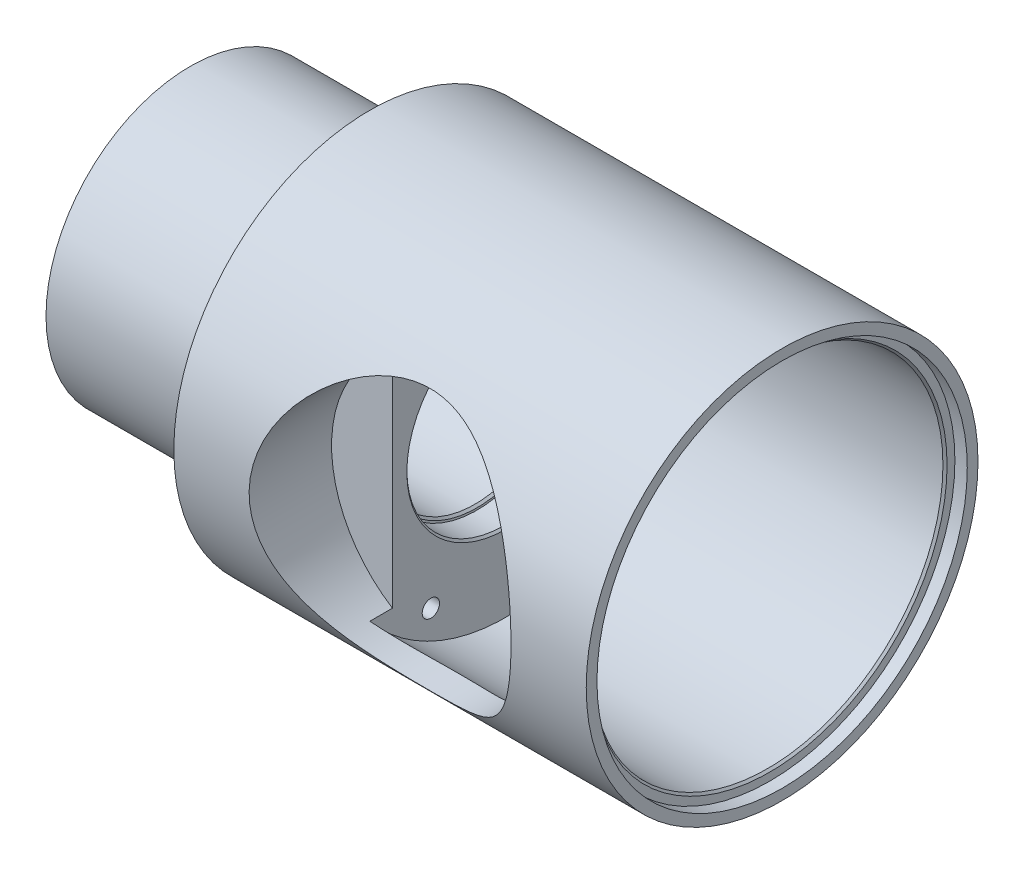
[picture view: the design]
ISO-10303-21;
HEADER;
FILE_DESCRIPTION(('STEP AP214'),'2;1');
FILE_NAME('part.step','',(''),(''),'','','');
FILE_SCHEMA(('AUTOMOTIVE_DESIGN { 1 0 10303 214 1 1 1 1 }'));
ENDSEC;
DATA;
#1=APPLICATION_CONTEXT('core data for automotive mechanical design processes');
#2=APPLICATION_PROTOCOL_DEFINITION('international standard','automotive_design',2000,#1);
#3=PRODUCT_CONTEXT('',#1,'mechanical');
#4=PRODUCT('Part','Part','',(#3));
#5=PRODUCT_RELATED_PRODUCT_CATEGORY('part','',(#4));
#6=PRODUCT_DEFINITION_FORMATION('','',#4);
#7=PRODUCT_DEFINITION_CONTEXT('part definition',#1,'design');
#8=PRODUCT_DEFINITION('design','',#6,#7);
#9=PRODUCT_DEFINITION_SHAPE('','',#8);
#10=(LENGTH_UNIT() NAMED_UNIT(*) SI_UNIT(.MILLI.,.METRE.));
#11=(NAMED_UNIT(*) PLANE_ANGLE_UNIT() SI_UNIT($,.RADIAN.));
#12=(NAMED_UNIT(*) SI_UNIT($,.STERADIAN.) SOLID_ANGLE_UNIT());
#13=UNCERTAINTY_MEASURE_WITH_UNIT(LENGTH_MEASURE(1.E-05),#10,'distance_accuracy_value','');
#14=(GEOMETRIC_REPRESENTATION_CONTEXT(3) GLOBAL_UNCERTAINTY_ASSIGNED_CONTEXT((#13)) GLOBAL_UNIT_ASSIGNED_CONTEXT((#10,
#11,#12)) REPRESENTATION_CONTEXT('',''));
#15=CARTESIAN_POINT('',(0.,0.,0.));
#16=DIRECTION('',(0.,0.,1.));
#17=DIRECTION('',(1.,0.,0.));
#18=AXIS2_PLACEMENT_3D('',#15,#16,#17);
#19=CARTESIAN_POINT('',(100.,0.,0.));
#20=DIRECTION('',(-1.,0.,0.));
#21=DIRECTION('',(0.,0.,1.));
#22=AXIS2_PLACEMENT_3D('',#19,#20,#21);
#23=CYLINDRICAL_SURFACE('',#22,42.5);
#24=CARTESIAN_POINT('',(96.5,0.,0.));
#25=DIRECTION('',(1.,0.,0.));
#26=DIRECTION('',(0.,0.,-1.));
#27=AXIS2_PLACEMENT_3D('',#24,#25,#26);
#28=CIRCLE('',#27,42.5);
#29=CARTESIAN_POINT('',(96.5,0.,-42.5));
#30=VERTEX_POINT('',#29);
#31=EDGE_CURVE('E47',#30,#30,#28,.T.);
#32=ORIENTED_EDGE('',*,*,#31,.T.);
#33=EDGE_LOOP('',(#32));
#34=FACE_BOUND('',#33,.T.);
#35=CARTESIAN_POINT('',(33.,26.8153407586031,32.9725264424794));
#36=CARTESIAN_POINT('',(33.3044816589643,27.0083646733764,32.815549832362));
#37=CARTESIAN_POINT('',(33.612655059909,27.1964727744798,32.6597490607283));
#38=CARTESIAN_POINT('',(34.236438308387,27.5627200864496,32.3512561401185));
#39=CARTESIAN_POINT('',(34.5520488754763,27.7408583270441,32.1985642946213));
#40=CARTESIAN_POINT('',(35.5108638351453,28.2605115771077,31.7459377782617));
#41=CARTESIAN_POINT('',(36.1652526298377,28.5867577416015,31.4518681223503));
#42=CARTESIAN_POINT('',(37.5111254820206,29.2000660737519,30.8833788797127));
#43=CARTESIAN_POINT('',(38.2029549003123,29.4866231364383,30.6092305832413));
#44=CARTESIAN_POINT('',(39.6154730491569,30.013190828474,30.0930934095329));
#45=CARTESIAN_POINT('',(40.3361453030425,30.2532275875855,29.8510865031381));
#46=CARTESIAN_POINT('',(41.6673684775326,30.6433808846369,29.4498945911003));
#47=CARTESIAN_POINT('',(42.2733328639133,30.8019186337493,29.2836835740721));
#48=CARTESIAN_POINT('',(43.5013379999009,31.0841865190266,28.9838887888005));
#49=CARTESIAN_POINT('',(44.123378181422,31.2079178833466,28.8503038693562));
#50=CARTESIAN_POINT('',(45.3774268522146,31.4180904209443,28.6212811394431));
#51=CARTESIAN_POINT('',(46.0093698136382,31.5047152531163,28.5256556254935));
#52=CARTESIAN_POINT('',(47.2822072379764,31.6399366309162,28.3756004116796));
#53=CARTESIAN_POINT('',(47.9231013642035,31.6885346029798,28.3211691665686));
#54=CARTESIAN_POINT('',(49.212934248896,31.7468476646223,28.2557897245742));
#55=CARTESIAN_POINT('',(49.861898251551,31.7563176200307,28.2451156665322));
#56=CARTESIAN_POINT('',(51.1583574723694,31.7354856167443,28.2685191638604));
#57=CARTESIAN_POINT('',(51.8058527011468,31.7051839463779,28.3025963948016));
#58=CARTESIAN_POINT('',(53.0952798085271,31.6053910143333,28.413989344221));
#59=CARTESIAN_POINT('',(53.7371985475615,31.5358242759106,28.4913883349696));
#60=CARTESIAN_POINT('',(55.009649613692,31.3588706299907,28.6860316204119));
#61=CARTESIAN_POINT('',(55.6401803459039,31.2514784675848,28.8032814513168));
#62=CARTESIAN_POINT('',(57.0171653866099,30.9743953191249,29.1013135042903));
#63=CARTESIAN_POINT('',(57.7601713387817,30.7963592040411,29.2902654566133));
#64=CARTESIAN_POINT('',(59.2202971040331,30.3911696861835,29.7104659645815));
#65=CARTESIAN_POINT('',(59.9374105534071,30.1640043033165,29.9417248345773));
#66=CARTESIAN_POINT('',(61.3448167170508,29.6633874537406,30.4377683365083));
#67=CARTESIAN_POINT('',(62.0350577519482,29.3898517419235,30.7026137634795));
#68=CARTESIAN_POINT('',(63.3863525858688,28.799510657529,31.2570352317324));
#69=CARTESIAN_POINT('',(64.0474046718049,28.4827027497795,31.5466127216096));
#70=CARTESIAN_POINT('',(65.5558197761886,27.695215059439,32.2426020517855));
#71=CARTESIAN_POINT('',(66.3917215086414,27.2084714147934,32.655749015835));
#72=CARTESIAN_POINT('',(68.0105141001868,26.1650818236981,33.4975866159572));
#73=CARTESIAN_POINT('',(68.7933891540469,25.6084151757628,33.9262818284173));
#74=CARTESIAN_POINT('',(70.3053771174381,24.4269370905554,34.7866247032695));
#75=CARTESIAN_POINT('',(71.0344469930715,23.8020720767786,35.218274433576));
#76=CARTESIAN_POINT('',(72.4357046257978,22.4861112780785,36.072707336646));
#77=CARTESIAN_POINT('',(73.1078989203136,21.7950231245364,36.4954915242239));
#78=CARTESIAN_POINT('',(74.3963690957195,20.3427813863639,37.3245969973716));
#79=CARTESIAN_POINT('',(75.0122101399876,19.5811615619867,37.7307787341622));
#80=CARTESIAN_POINT('',(76.1774518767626,17.9936771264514,38.5131160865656));
#81=CARTESIAN_POINT('',(76.7268446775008,17.1678049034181,38.8892681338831));
#82=CARTESIAN_POINT('',(77.4952335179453,15.8846665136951,39.4226032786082));
#83=CARTESIAN_POINT('',(77.7418553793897,15.4500335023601,39.595071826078));
#84=CARTESIAN_POINT('',(78.2159513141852,14.5661932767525,39.9286738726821));
#85=CARTESIAN_POINT('',(78.4434266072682,14.1169869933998,40.0898080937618));
#86=CARTESIAN_POINT('',(78.8781436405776,13.204937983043,40.3993987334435));
#87=CARTESIAN_POINT('',(79.0853960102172,12.7421025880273,40.5478618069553));
#88=CARTESIAN_POINT('',(79.4788601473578,11.8033226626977,40.8310181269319));
#89=CARTESIAN_POINT('',(79.6650668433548,11.3273750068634,40.9657080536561));
#90=CARTESIAN_POINT('',(80.087375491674,10.165412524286,41.2723723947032));
#91=CARTESIAN_POINT('',(80.3125546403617,9.47341468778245,41.4369361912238));
#92=CARTESIAN_POINT('',(80.7162066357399,8.06911355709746,41.7331287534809));
#93=CARTESIAN_POINT('',(80.8946904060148,7.35681505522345,41.8647652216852));
#94=CARTESIAN_POINT('',(81.1255926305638,6.27659556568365,42.0355490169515));
#95=CARTESIAN_POINT('',(81.1964172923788,5.91459909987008,42.0880276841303));
#96=CARTESIAN_POINT('',(81.3255693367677,5.18725605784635,42.1838466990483));
#97=CARTESIAN_POINT('',(81.3838990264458,4.82191011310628,42.2271887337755));
#98=CARTESIAN_POINT('',(81.5398253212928,3.72160807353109,42.3431592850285));
#99=CARTESIAN_POINT('',(81.6183742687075,2.98231724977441,42.401743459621));
#100=CARTESIAN_POINT('',(81.7235000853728,1.49618226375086,42.4801924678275));
#101=CARTESIAN_POINT('',(81.7499437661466,0.74932363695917,42.4999580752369));
#102=CARTESIAN_POINT('',(81.7500560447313,-0.744422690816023,42.5000417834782));
#103=CARTESIAN_POINT('',(81.7237248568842,-1.49131039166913,42.4803600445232));
#104=CARTESIAN_POINT('',(81.618697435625,-2.97943207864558,42.4019847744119));
#105=CARTESIAN_POINT('',(81.5399924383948,-3.72066509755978,42.3432847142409));
#106=CARTESIAN_POINT('',(81.3314378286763,-5.19186855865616,42.188169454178));
#107=CARTESIAN_POINT('',(81.2015885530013,-5.92183907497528,42.0917545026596));
#108=CARTESIAN_POINT('',(80.8979550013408,-7.34078972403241,41.867183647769));
#109=CARTESIAN_POINT('',(80.7258286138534,-8.03031734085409,41.7402285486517));
#110=CARTESIAN_POINT('',(80.3378281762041,-9.39035484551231,41.4554455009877));
#111=CARTESIAN_POINT('',(80.1219554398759,-10.0608653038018,41.2976184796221));
#112=CARTESIAN_POINT('',(79.648862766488,-11.3797338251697,40.9538295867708));
#113=CARTESIAN_POINT('',(79.3916390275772,-12.0280898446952,40.7678651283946));
#114=CARTESIAN_POINT('',(78.8383817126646,-13.3000503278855,40.370814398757));
#115=CARTESIAN_POINT('',(78.542345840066,-13.9236533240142,40.1597266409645));
#116=CARTESIAN_POINT('',(77.8800029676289,-15.2100737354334,39.691578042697));
#117=CARTESIAN_POINT('',(77.5095594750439,-15.8698499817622,39.4320142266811));
#118=CARTESIAN_POINT('',(76.7272772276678,-17.1546188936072,38.8902971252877));
#119=CARTESIAN_POINT('',(76.3154359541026,-17.7796094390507,38.6081424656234));
#120=CARTESIAN_POINT('',(75.4529052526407,-18.9938708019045,38.025473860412));
#121=CARTESIAN_POINT('',(75.0021884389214,-19.5831159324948,37.7249470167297));
#122=CARTESIAN_POINT('',(74.0645874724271,-20.7244702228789,37.1101951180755));
#123=CARTESIAN_POINT('',(73.5777015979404,-21.2765776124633,36.795969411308));
#124=CARTESIAN_POINT('',(72.4710049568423,-22.4474122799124,36.0959193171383));
#125=CARTESIAN_POINT('',(71.8438326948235,-23.0580194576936,35.7081218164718));
#126=CARTESIAN_POINT('',(70.5429813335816,-24.2241970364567,34.9275066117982));
#127=CARTESIAN_POINT('',(69.8692932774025,-24.7797567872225,34.5346879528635));
#128=CARTESIAN_POINT('',(68.4767492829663,-25.8347768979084,33.7527119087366));
#129=CARTESIAN_POINT('',(67.7578733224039,-26.3342121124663,33.3635562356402));
#130=CARTESIAN_POINT('',(66.2761509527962,-27.2748840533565,32.599045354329));
#131=CARTESIAN_POINT('',(65.5133145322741,-27.7161339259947,32.2236870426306));
#132=CARTESIAN_POINT('',(64.0996929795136,-28.4563742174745,31.5702079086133));
#133=CARTESIAN_POINT('',(63.4566756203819,-28.766225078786,31.28756252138));
#134=CARTESIAN_POINT('',(62.1429067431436,-29.3449733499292,30.7454014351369));
#135=CARTESIAN_POINT('',(61.4721556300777,-29.613871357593,30.4858853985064));
#136=CARTESIAN_POINT('',(60.1048873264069,-30.1078266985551,29.9981520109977));
#137=CARTESIAN_POINT('',(59.4084130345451,-30.3329534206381,29.7698852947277));
#138=CARTESIAN_POINT('',(57.990637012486,-30.736867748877,29.3526733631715));
#139=CARTESIAN_POINT('',(57.2693416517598,-30.9156671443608,29.163718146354));
#140=CARTESIAN_POINT('',(55.9476954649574,-31.1937604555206,28.8657650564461));
#141=CARTESIAN_POINT('',(55.3510652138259,-31.3017514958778,28.7483654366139));
#142=CARTESIAN_POINT('',(54.146828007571,-31.4839158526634,28.5487546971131));
#143=CARTESIAN_POINT('',(53.5392224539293,-31.5580934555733,28.4665391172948));
#144=CARTESIAN_POINT('',(52.3179935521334,-31.6711958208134,28.3406521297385));
#145=CARTESIAN_POINT('',(51.7043850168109,-31.710192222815,28.2969023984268));
#146=CARTESIAN_POINT('',(50.4743654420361,-31.7524191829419,28.2495117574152));
#147=CARTESIAN_POINT('',(49.8579543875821,-31.7556495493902,28.2458710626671));
#148=CARTESIAN_POINT('',(48.6278025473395,-31.7262933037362,28.2788397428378));
#149=CARTESIAN_POINT('',(48.0140594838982,-31.6937485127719,28.3154021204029));
#150=CARTESIAN_POINT('',(46.793028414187,-31.5935619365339,28.4271422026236));
#151=CARTESIAN_POINT('',(46.1857405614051,-31.525919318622,28.5023208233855));
#152=CARTESIAN_POINT('',(44.9784122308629,-31.3563342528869,28.688781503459));
#153=CARTESIAN_POINT('',(44.3784246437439,-31.2542183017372,28.8002460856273));
#154=CARTESIAN_POINT('',(43.1919250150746,-31.0173947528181,29.0551443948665));
#155=CARTESIAN_POINT('',(42.6054135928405,-30.882685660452,29.1985795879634));
#156=CARTESIAN_POINT('',(41.2005638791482,-30.5182001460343,29.580156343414));
#157=CARTESIAN_POINT('',(40.3902262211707,-30.2723952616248,29.8325796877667));
#158=CARTESIAN_POINT('',(38.8041722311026,-29.7224123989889,30.3805671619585));
#159=CARTESIAN_POINT('',(38.0284916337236,-29.4181758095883,30.6761745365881));
#160=CARTESIAN_POINT('',(36.5222538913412,-28.759015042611,31.2949033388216));
#161=CARTESIAN_POINT('',(35.7912883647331,-28.4046973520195,31.6176791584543));
#162=CARTESIAN_POINT('',(34.7230823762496,-27.8359579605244,32.1165532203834));
#163=CARTESIAN_POINT('',(34.3720780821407,-27.6403947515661,32.285109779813));
#164=CARTESIAN_POINT('',(33.6792081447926,-27.2370112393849,32.6261397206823));
#165=CARTESIAN_POINT('',(33.3373412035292,-27.0291926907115,32.7986125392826));
#166=CARTESIAN_POINT('',(33.,-26.8153407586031,32.9725264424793));
#167=B_SPLINE_CURVE_WITH_KNOTS('',3,(#35,#36,#37,#38,#39,#40,#41,#42,#43,#44,#45,#46,#47,#48,
#49,#50,#51,#52,#53,#54,#55,#56,#57,#58,#59,#60,#61,#62,#63,#64,#65,#66,#67,#68,#69,#70,#71,#72,
#73,#74,#75,#76,#77,#78,#79,#80,#81,#82,#83,#84,#85,#86,#87,#88,#89,#90,#91,#92,#93,#94,#95,#96,
#97,#98,#99,#100,#101,#102,#103,#104,#105,#106,#107,#108,#109,#110,#111,#112,#113,#114,#115,
#116,#117,#118,#119,#120,#121,#122,#123,#124,#125,#126,#127,#128,#129,#130,#131,#132,#133,#134,
#135,#136,#137,#138,#139,#140,#141,#142,#143,#144,#145,#146,#147,#148,#149,#150,#151,#152,#153,
#154,#155,#156,#157,#158,#159,#160,#161,#162,#163,#164,#165,#166),.UNSPECIFIED.,.F.,.F.,(4,2,2,
2,2,2,2,2,2,2,2,2,2,2,2,2,2,2,2,2,2,2,2,2,2,2,2,2,2,2,2,2,2,2,2,2,2,2,2,2,2,2,2,2,2,2,2,2,2,2,2,
2,2,2,2,2,2,2,2,2,2,2,2,2,2,4),(0.,1.17950720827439,2.35912900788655,4.72146779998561,
7.11154645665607,9.50027872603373,11.4426474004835,13.3849475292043,15.3175199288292,
17.2500198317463,19.1946085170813,21.1391831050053,23.0875084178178,25.0361045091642,
27.3937212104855,29.751913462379,32.114436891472,34.4770987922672,37.6283786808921,
40.7805937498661,43.9353032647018,47.0896496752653,50.2665812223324,53.4438897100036,
55.0292971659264,56.6146035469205,58.1990721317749,59.7839217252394,62.0197684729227,
64.2550917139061,65.3725185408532,66.4897388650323,68.723961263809,70.9638872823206,
73.2038042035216,75.444096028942,77.684373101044,79.8478870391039,82.0113360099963,
84.1749840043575,86.3387600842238,88.7362833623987,91.1339526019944,93.5333248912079,
95.9328114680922,98.8020819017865,101.671906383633,104.543011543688,107.41346689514,
109.714852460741,112.016204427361,114.31387786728,116.610966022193,118.461882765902,
120.312564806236,122.15946973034,124.006384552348,125.851142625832,127.695944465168,
129.550173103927,131.404486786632,134.050955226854,136.700092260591,139.319530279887,
140.626480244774,141.933243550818),.UNSPECIFIED.);
#168=CARTESIAN_POINT('',(33.,26.8153407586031,32.9725264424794));
#169=VERTEX_POINT('',#168);
#170=CARTESIAN_POINT('',(33.,-26.8153407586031,32.9725264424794));
#171=VERTEX_POINT('',#170);
#172=EDGE_CURVE('E60',#169,#171,#167,.T.);
#173=ORIENTED_EDGE('',*,*,#172,.F.);
#174=CARTESIAN_POINT('',(33.,0.,0.));
#175=DIRECTION('',(-1.,0.,0.));
#176=DIRECTION('',(0.,0.,1.));
#177=AXIS2_PLACEMENT_3D('',#174,#175,#176);
#178=CIRCLE('',#177,42.5);
#179=EDGE_CURVE('E181',#169,#171,#178,.T.);
#180=ORIENTED_EDGE('',*,*,#179,.T.);
#181=EDGE_LOOP('',(#173,#180));
#182=FACE_BOUND('',#181,.T.);
#183=ADVANCED_FACE('F39',(#34,#182),#23,.F.);
#184=CARTESIAN_POINT('',(-46.,0.,0.));
#185=DIRECTION('',(1.,0.,0.));
#186=DIRECTION('',(0.,0.,-1.));
#187=AXIS2_PLACEMENT_3D('',#184,#185,#186);
#188=CYLINDRICAL_SURFACE('',#187,35.);
#189=CARTESIAN_POINT('',(0.,0.,0.));
#190=DIRECTION('',(-1.,0.,0.));
#191=DIRECTION('',(0.,0.,1.));
#192=AXIS2_PLACEMENT_3D('',#189,#190,#191);
#193=CIRCLE('',#192,35.);
#194=CARTESIAN_POINT('',(0.,0.,35.));
#195=VERTEX_POINT('',#194);
#196=EDGE_CURVE('E95',#195,#195,#193,.T.);
#197=ORIENTED_EDGE('',*,*,#196,.T.);
#198=EDGE_LOOP('',(#197));
#199=FACE_BOUND('',#198,.T.);
#200=CARTESIAN_POINT('',(-43.5,0.,0.));
#201=DIRECTION('',(-1.,0.,0.));
#202=DIRECTION('',(0.,0.,1.));
#203=AXIS2_PLACEMENT_3D('',#200,#201,#202);
#204=CIRCLE('',#203,35.);
#205=CARTESIAN_POINT('',(-43.5,0.,35.));
#206=VERTEX_POINT('',#205);
#207=EDGE_CURVE('E213',#206,#206,#204,.T.);
#208=ORIENTED_EDGE('',*,*,#207,.F.);
#209=EDGE_LOOP('',(#208));
#210=FACE_BOUND('',#209,.T.);
#211=ADVANCED_FACE('F168',(#199,#210),#188,.T.);
#212=CARTESIAN_POINT('',(-23.,0.,0.));
#213=DIRECTION('',(-1.,0.,0.));
#214=DIRECTION('',(0.,0.,1.));
#215=AXIS2_PLACEMENT_3D('',#212,#213,#214);
#216=CYLINDRICAL_SURFACE('',#215,21.);
#217=CARTESIAN_POINT('',(-23.,0.,0.));
#218=DIRECTION('',(-1.,0.,0.));
#219=DIRECTION('',(0.,0.,1.));
#220=AXIS2_PLACEMENT_3D('',#217,#218,#219);
#221=CIRCLE('',#220,21.);
#222=CARTESIAN_POINT('',(-23.,0.,21.));
#223=VERTEX_POINT('',#222);
#224=EDGE_CURVE('E92',#223,#223,#221,.T.);
#225=ORIENTED_EDGE('',*,*,#224,.F.);
#226=EDGE_LOOP('',(#225));
#227=FACE_BOUND('',#226,.T.);
#228=CARTESIAN_POINT('',(-43.5,0.,0.));
#229=DIRECTION('',(-1.,0.,0.));
#230=DIRECTION('',(0.,0.,1.));
#231=AXIS2_PLACEMENT_3D('',#228,#229,#230);
#232=CIRCLE('',#231,21.);
#233=CARTESIAN_POINT('',(-43.5,0.,21.));
#234=VERTEX_POINT('',#233);
#235=EDGE_CURVE('E210',#234,#234,#232,.F.);
#236=ORIENTED_EDGE('',*,*,#235,.F.);
#237=EDGE_LOOP('',(#236));
#238=FACE_BOUND('',#237,.T.);
#239=ADVANCED_FACE('F173',(#227,#238),#216,.F.);
#240=CARTESIAN_POINT('',(100.,0.,0.));
#241=DIRECTION('',(1.,0.,0.));
#242=DIRECTION('',(0.,0.,-1.));
#243=AXIS2_PLACEMENT_3D('',#240,#241,#242);
#244=PLANE('',#243);
#245=CARTESIAN_POINT('',(100.,0.,0.));
#246=DIRECTION('',(1.,0.,0.));
#247=DIRECTION('',(0.,0.,-1.));
#248=AXIS2_PLACEMENT_3D('',#245,#246,#247);
#249=CIRCLE('',#248,44.9);
#250=CARTESIAN_POINT('',(100.,0.,-44.9));
#251=VERTEX_POINT('',#250);
#252=EDGE_CURVE('E225',#251,#251,#249,.T.);
#253=ORIENTED_EDGE('',*,*,#252,.F.);
#254=EDGE_LOOP('',(#253));
#255=FACE_BOUND('',#254,.T.);
#256=CARTESIAN_POINT('',(100.,0.,0.));
#257=DIRECTION('',(1.,0.,0.));
#258=DIRECTION('',(0.,0.,-1.));
#259=AXIS2_PLACEMENT_3D('',#256,#257,#258);
#260=CIRCLE('',#259,47.5);
#261=CARTESIAN_POINT('',(100.,0.,-47.5));
#262=VERTEX_POINT('',#261);
#263=EDGE_CURVE('E189',#262,#262,#260,.T.);
#264=ORIENTED_EDGE('',*,*,#263,.T.);
#265=EDGE_LOOP('',(#264));
#266=FACE_BOUND('',#265,.T.);
#267=ADVANCED_FACE('F254',(#255,#266),#244,.T.);
#268=CARTESIAN_POINT('',(0.,0.,0.));
#269=DIRECTION('',(1.,0.,0.));
#270=DIRECTION('',(0.,0.,-1.));
#271=AXIS2_PLACEMENT_3D('',#268,#269,#270);
#272=PLANE('',#271);
#273=CARTESIAN_POINT('',(0.,0.,0.));
#274=DIRECTION('',(1.,0.,0.));
#275=DIRECTION('',(0.,0.,-1.));
#276=AXIS2_PLACEMENT_3D('',#273,#274,#275);
#277=CIRCLE('',#276,47.5);
#278=CARTESIAN_POINT('',(0.,0.,-47.5));
#279=VERTEX_POINT('',#278);
#280=EDGE_CURVE('E187',#279,#279,#277,.T.);
#281=ORIENTED_EDGE('',*,*,#280,.F.);
#282=EDGE_LOOP('',(#281));
#283=FACE_BOUND('',#282,.T.);
#284=ORIENTED_EDGE('',*,*,#196,.F.);
#285=EDGE_LOOP('',(#284));
#286=FACE_BOUND('',#285,.T.);
#287=ADVANCED_FACE('F163',(#283,#286),#272,.F.);
#288=CARTESIAN_POINT('',(100.,0.,0.));
#289=DIRECTION('',(-1.,0.,0.));
#290=DIRECTION('',(0.,0.,1.));
#291=AXIS2_PLACEMENT_3D('',#288,#289,#290);
#292=CYLINDRICAL_SURFACE('',#291,47.5);
#293=CARTESIAN_POINT('',(81.75,0.,47.5));
#294=CARTESIAN_POINT('',(81.7500004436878,-0.797202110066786,47.500000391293));
#295=CARTESIAN_POINT('',(81.7199353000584,-1.59439947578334,47.4798883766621));
#296=CARTESIAN_POINT('',(81.6001519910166,-3.18226729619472,47.3999485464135));
#297=CARTESIAN_POINT('',(81.5104343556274,-3.97293780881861,47.3401210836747));
#298=CARTESIAN_POINT('',(81.2726769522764,-5.54183673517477,47.1821993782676));
#299=CARTESIAN_POINT('',(81.1246161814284,-6.32006056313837,47.0840913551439));
#300=CARTESIAN_POINT('',(80.772297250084,-7.85816597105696,46.851939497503));
#301=CARTESIAN_POINT('',(80.5680382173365,-8.61804726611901,46.7178951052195));
#302=CARTESIAN_POINT('',(80.107098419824,-10.1110159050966,46.4176094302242));
#303=CARTESIAN_POINT('',(79.8506726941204,-10.8442138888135,46.2515249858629));
#304=CARTESIAN_POINT('',(79.2877461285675,-12.2836355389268,45.8902276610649));
#305=CARTESIAN_POINT('',(78.9812455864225,-12.9898593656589,45.6950149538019));
#306=CARTESIAN_POINT('',(78.321197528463,-14.372158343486,45.2792670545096));
#307=CARTESIAN_POINT('',(77.9676497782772,-15.0482333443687,45.0587317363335));
#308=CARTESIAN_POINT('',(77.2164491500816,-16.367769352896,44.5963560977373));
#309=CARTESIAN_POINT('',(76.8187941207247,-17.0112287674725,44.3545147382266));
#310=CARTESIAN_POINT('',(75.9465363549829,-18.3168620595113,43.8323849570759));
#311=CARTESIAN_POINT('',(75.4682660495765,-18.9759769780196,43.5505758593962));
#312=CARTESIAN_POINT('',(74.4661227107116,-20.2516512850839,42.9722140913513));
#313=CARTESIAN_POINT('',(73.9422476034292,-20.8682087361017,42.6756607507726));
#314=CARTESIAN_POINT('',(72.85078583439,-22.0580305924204,42.073014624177));
#315=CARTESIAN_POINT('',(72.2831415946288,-22.6312359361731,41.7669095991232));
#316=CARTESIAN_POINT('',(71.1068978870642,-23.7320520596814,41.1513967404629));
#317=CARTESIAN_POINT('',(70.4982960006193,-24.259660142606,40.841988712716));
#318=CARTESIAN_POINT('',(69.142006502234,-25.347928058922,40.1771197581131));
#319=CARTESIAN_POINT('',(68.3875818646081,-25.9005256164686,39.8221504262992));
#320=CARTESIAN_POINT('',(66.8280869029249,-26.939863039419,39.1265248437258));
#321=CARTESIAN_POINT('',(66.0230050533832,-27.4265878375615,38.7858718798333));
#322=CARTESIAN_POINT('',(64.3656084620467,-28.3298662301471,38.131082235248));
#323=CARTESIAN_POINT('',(63.5133598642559,-28.7465149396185,37.8169099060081));
#324=CARTESIAN_POINT('',(61.7636735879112,-29.5057088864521,37.2275996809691));
#325=CARTESIAN_POINT('',(60.8662579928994,-29.8482899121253,36.9524429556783));
#326=CARTESIAN_POINT('',(59.2971336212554,-30.3660442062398,36.5271244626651));
#327=CARTESIAN_POINT('',(58.635437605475,-30.5609551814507,36.3638542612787));
#328=CARTESIAN_POINT('',(57.2941343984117,-30.9085391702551,36.0688818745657));
#329=CARTESIAN_POINT('',(56.614530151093,-31.0612190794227,35.9371745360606));
#330=CARTESIAN_POINT('',(55.2418790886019,-31.3220764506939,35.7100475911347));
#331=CARTESIAN_POINT('',(54.5488539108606,-31.4303201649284,35.6145739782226));
#332=CARTESIAN_POINT('',(53.1528202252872,-31.6008960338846,35.4633113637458));
#333=CARTESIAN_POINT('',(52.4498116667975,-31.663227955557,35.4075225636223));
#334=CARTESIAN_POINT('',(51.0361244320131,-31.7410168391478,35.3378076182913));
#335=CARTESIAN_POINT('',(50.3254259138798,-31.7562750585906,35.3240589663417));
#336=CARTESIAN_POINT('',(48.9050808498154,-31.7390624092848,35.3395251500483));
#337=CARTESIAN_POINT('',(48.1954343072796,-31.7065913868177,35.3687401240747));
#338=CARTESIAN_POINT('',(46.7823583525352,-31.5944941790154,35.4689092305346));
#339=CARTESIAN_POINT('',(46.0789339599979,-31.5148329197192,35.5398944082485));
#340=CARTESIAN_POINT('',(44.6839107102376,-31.3097240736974,35.7207191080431));
#341=CARTESIAN_POINT('',(43.9923120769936,-31.1842756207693,35.8305593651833));
#342=CARTESIAN_POINT('',(42.6563084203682,-30.8962500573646,36.0791647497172));
#343=CARTESIAN_POINT('',(42.0111891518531,-30.7356259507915,36.216383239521));
#344=CARTESIAN_POINT('',(40.7380318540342,-30.376243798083,36.5183359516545));
#345=CARTESIAN_POINT('',(40.1100005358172,-30.1774710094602,36.6830808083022));
#346=CARTESIAN_POINT('',(38.8732274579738,-29.743687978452,37.0356732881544));
#347=CARTESIAN_POINT('',(38.2644876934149,-29.5086740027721,37.2235232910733));
#348=CARTESIAN_POINT('',(37.0679273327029,-29.0042327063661,37.6179074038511));
#349=CARTESIAN_POINT('',(36.4801021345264,-28.7348130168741,37.8244373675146));
#350=CARTESIAN_POINT('',(35.2083604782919,-28.1046463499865,38.2957382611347));
#351=CARTESIAN_POINT('',(34.5293280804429,-27.7364838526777,38.5637910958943));
#352=CARTESIAN_POINT('',(33.2041097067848,-26.9546394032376,39.1142691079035));
#353=CARTESIAN_POINT('',(32.5579268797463,-26.5409530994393,39.3966956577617));
#354=CARTESIAN_POINT('',(31.2988777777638,-25.669385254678,39.9700515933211));
#355=CARTESIAN_POINT('',(30.6860489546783,-25.2114555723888,40.2609899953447));
#356=CARTESIAN_POINT('',(29.49570008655,-24.2532479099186,40.845379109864));
#357=CARTESIAN_POINT('',(28.9181824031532,-23.7529671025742,41.1388299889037));
#358=CARTESIAN_POINT('',(27.6779131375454,-22.5976407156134,41.7866669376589));
#359=CARTESIAN_POINT('',(27.02404155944,-21.9326374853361,42.1403848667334));
#360=CARTESIAN_POINT('',(25.7741481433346,-20.5436983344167,42.8346755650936));
#361=CARTESIAN_POINT('',(25.1781370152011,-19.8197515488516,43.1752458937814));
#362=CARTESIAN_POINT('',(24.0487019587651,-18.3160075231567,43.8343161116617));
#363=CARTESIAN_POINT('',(23.5152327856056,-17.5362513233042,44.1528318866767));
#364=CARTESIAN_POINT('',(22.5155363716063,-15.9237564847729,44.7596412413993));
#365=CARTESIAN_POINT('',(22.049290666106,-15.0910324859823,45.0479431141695));
#366=CARTESIAN_POINT('',(21.2737886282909,-13.5448153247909,45.533616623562));
#367=CARTESIAN_POINT('',(20.9516649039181,-12.8398720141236,45.7377427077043));
#368=CARTESIAN_POINT('',(20.3576335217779,-11.4016532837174,46.1172977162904));
#369=CARTESIAN_POINT('',(20.0857200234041,-10.6683811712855,46.2927299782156));
#370=CARTESIAN_POINT('',(19.5953164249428,-9.17784356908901,46.6111308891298));
#371=CARTESIAN_POINT('',(19.3767903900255,-8.42059460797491,46.7541213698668));
#372=CARTESIAN_POINT('',(18.9957128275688,-6.88632018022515,47.0046028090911));
#373=CARTESIAN_POINT('',(18.8331621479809,-6.10929441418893,47.1120932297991));
#374=CARTESIAN_POINT('',(18.565753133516,-4.53749871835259,47.2894205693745));
#375=CARTESIAN_POINT('',(18.4611543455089,-3.74266528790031,47.3590880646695));
#376=CARTESIAN_POINT('',(18.3123705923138,-2.14485126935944,47.4583003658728));
#377=CARTESIAN_POINT('',(18.2681857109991,-1.34187066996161,47.4878451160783));
#378=CARTESIAN_POINT('',(18.2409367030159,0.26555130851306,47.506057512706));
#379=CARTESIAN_POINT('',(18.2578695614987,1.06999261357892,47.4947271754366));
#380=CARTESIAN_POINT('',(18.3525793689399,2.67364401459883,47.4314819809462));
#381=CARTESIAN_POINT('',(18.4303536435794,3.47285433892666,47.3795689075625));
#382=CARTESIAN_POINT('',(18.6378017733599,5.00276919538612,47.2416074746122));
#383=CARTESIAN_POINT('',(18.7633628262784,5.73428294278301,47.1582680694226));
#384=CARTESIAN_POINT('',(19.0642420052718,7.18249990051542,46.9595130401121));
#385=CARTESIAN_POINT('',(19.2395572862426,7.89920395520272,46.8440992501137));
#386=CARTESIAN_POINT('',(19.6378916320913,9.31369090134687,46.5834997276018));
#387=CARTESIAN_POINT('',(19.8609138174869,10.0114725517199,46.4383120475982));
#388=CARTESIAN_POINT('',(20.3522941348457,11.3845433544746,46.1209149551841));
#389=CARTESIAN_POINT('',(20.6206546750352,12.0598313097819,45.9487041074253));
#390=CARTESIAN_POINT('',(21.2174449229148,13.4243832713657,45.5693622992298));
#391=CARTESIAN_POINT('',(21.5484976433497,14.1120906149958,45.3607637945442));
#392=CARTESIAN_POINT('',(22.2557086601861,15.456182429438,44.9205589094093));
#393=CARTESIAN_POINT('',(22.6318682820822,16.1125659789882,44.6889518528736));
#394=CARTESIAN_POINT('',(23.4266347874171,17.3921338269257,44.2066897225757));
#395=CARTESIAN_POINT('',(23.8452600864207,18.0153035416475,43.9560263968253));
#396=CARTESIAN_POINT('',(24.7223490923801,19.2265972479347,43.4398592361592));
#397=CARTESIAN_POINT('',(25.1808172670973,19.8147172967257,43.1743537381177));
#398=CARTESIAN_POINT('',(25.9344301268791,20.714638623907,42.7467823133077));
#399=CARTESIAN_POINT('',(26.2171472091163,21.0386024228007,42.5881876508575));
#400=CARTESIAN_POINT('',(26.7947387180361,21.6740085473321,42.2683551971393));
#401=CARTESIAN_POINT('',(27.0896107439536,21.9854533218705,42.1071179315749));
#402=CARTESIAN_POINT('',(27.992143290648,22.9009016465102,41.620621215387));
#403=CARTESIAN_POINT('',(28.6176957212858,23.4859899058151,41.2925908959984));
#404=CARTESIAN_POINT('',(29.9143340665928,24.6041072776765,40.6362962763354));
#405=CARTESIAN_POINT('',(30.5854516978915,25.137099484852,40.3080319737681));
#406=CARTESIAN_POINT('',(31.9710227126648,26.1486918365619,39.65925889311));
#407=CARTESIAN_POINT('',(32.6854718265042,26.6272973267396,39.338749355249));
#408=CARTESIAN_POINT('',(34.0969389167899,27.4915216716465,38.7391307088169));
#409=CARTESIAN_POINT('',(34.7907395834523,27.8815229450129,38.4587648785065));
#410=CARTESIAN_POINT('',(36.2123143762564,28.6111944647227,37.9190648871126));
#411=CARTESIAN_POINT('',(36.9400891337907,28.9508637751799,37.6597311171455));
#412=CARTESIAN_POINT('',(38.4266205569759,29.5764888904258,37.1704031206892));
#413=CARTESIAN_POINT('',(39.1853300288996,29.8625230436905,36.9403662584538));
#414=CARTESIAN_POINT('',(40.7318158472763,30.37806933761,36.5175879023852));
#415=CARTESIAN_POINT('',(41.51958530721,30.6075947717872,36.3248376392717));
#416=CARTESIAN_POINT('',(42.9733290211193,30.9700230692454,36.0160172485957));
#417=CARTESIAN_POINT('',(43.6352095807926,31.1129213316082,35.8923696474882));
#418=CARTESIAN_POINT('',(44.9721390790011,31.356731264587,35.6795697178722));
#419=CARTESIAN_POINT('',(45.6471864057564,31.45764804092,35.59041319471));
#420=CARTESIAN_POINT('',(47.0056588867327,31.6158750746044,35.4499322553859));
#421=CARTESIAN_POINT('',(47.6890754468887,31.6732267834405,35.398571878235));
#422=CARTESIAN_POINT('',(49.0600504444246,31.7435045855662,35.3355654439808));
#423=CARTESIAN_POINT('',(49.7476089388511,31.7564300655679,35.323919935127));
#424=CARTESIAN_POINT('',(51.12211260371,31.7376136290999,35.3408266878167));
#425=CARTESIAN_POINT('',(51.8090569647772,31.7058392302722,35.3694081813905));
#426=CARTESIAN_POINT('',(53.1766664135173,31.5981303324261,35.4656639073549));
#427=CARTESIAN_POINT('',(53.8573315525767,31.5221961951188,35.5333378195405));
#428=CARTESIAN_POINT('',(55.208543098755,31.3273059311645,35.7052758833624));
#429=CARTESIAN_POINT('',(55.8790770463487,31.2083007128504,35.8095817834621));
#430=CARTESIAN_POINT('',(57.2054414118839,30.9290099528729,36.051079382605));
#431=CARTESIAN_POINT('',(57.8612699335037,30.7687191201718,36.1882752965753));
#432=CARTESIAN_POINT('',(59.3256338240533,30.3614005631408,36.5311326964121));
#433=CARTESIAN_POINT('',(60.1289274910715,30.1026476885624,36.7453101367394));
#434=CARTESIAN_POINT('',(61.703216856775,29.5262670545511,37.2100312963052));
#435=CARTESIAN_POINT('',(62.4742036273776,29.2086231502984,37.4605849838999));
#436=CARTESIAN_POINT('',(63.981945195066,28.5176463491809,37.9892513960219));
#437=CARTESIAN_POINT('',(64.7186622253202,28.1442538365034,38.2673935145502));
#438=CARTESIAN_POINT('',(66.1551691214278,27.3449932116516,38.8425504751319));
#439=CARTESIAN_POINT('',(66.8549609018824,26.9191278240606,39.139564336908));
#440=CARTESIAN_POINT('',(68.2288148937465,26.0089261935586,39.7503665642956));
#441=CARTESIAN_POINT('',(68.9021659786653,25.5236576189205,40.06436311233));
#442=CARTESIAN_POINT('',(70.2076518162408,24.503056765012,40.6965670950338));
#443=CARTESIAN_POINT('',(70.8397867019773,23.9677246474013,41.0147745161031));
#444=CARTESIAN_POINT('',(72.0612147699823,22.8484485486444,41.6486752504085));
#445=CARTESIAN_POINT('',(72.6504956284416,22.2644906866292,41.9643678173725));
#446=CARTESIAN_POINT('',(73.7837632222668,21.0495902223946,42.5867433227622));
#447=CARTESIAN_POINT('',(74.3277460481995,20.4186435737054,42.8934254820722));
#448=CARTESIAN_POINT('',(75.4448467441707,19.0142659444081,43.5360658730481));
#449=CARTESIAN_POINT('',(76.0102951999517,18.2335898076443,43.8696086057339));
#450=CARTESIAN_POINT('',(77.0726104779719,16.6154435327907,44.5076784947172));
#451=CARTESIAN_POINT('',(77.5694673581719,15.7779651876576,44.812201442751));
#452=CARTESIAN_POINT('',(78.488047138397,14.051635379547,45.383114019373));
#453=CARTESIAN_POINT('',(78.9098566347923,13.1628447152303,45.6495475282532));
#454=CARTESIAN_POINT('',(79.6725646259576,11.3391943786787,46.1363450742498));
#455=CARTESIAN_POINT('',(80.0134902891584,10.4043503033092,46.3567245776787));
#456=CARTESIAN_POINT('',(80.5461670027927,8.69594301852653,46.7035772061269));
#457=CARTESIAN_POINT('',(80.754201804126,7.92944700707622,46.8400498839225));
#458=CARTESIAN_POINT('',(81.1130478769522,6.37766370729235,47.076437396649));
#459=CARTESIAN_POINT('',(81.2638678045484,5.59237928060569,47.1763577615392));
#460=CARTESIAN_POINT('',(81.5060166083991,4.0092669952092,47.337177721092));
#461=CARTESIAN_POINT('',(81.5973854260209,3.21144792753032,47.3981035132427));
#462=CARTESIAN_POINT('',(81.7193775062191,1.60908438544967,47.4795148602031));
#463=CARTESIAN_POINT('',(81.7499995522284,0.804539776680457,47.4999996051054));
#464=CARTESIAN_POINT('',(81.75,0.,47.5));
#465=B_SPLINE_CURVE_WITH_KNOTS('',3,(#293,#294,#295,#296,#297,#298,#299,#300,#301,#302,#303,
#304,#305,#306,#307,#308,#309,#310,#311,#312,#313,#314,#315,#316,#317,#318,#319,#320,#321,#322,
#323,#324,#325,#326,#327,#328,#329,#330,#331,#332,#333,#334,#335,#336,#337,#338,#339,#340,#341,
#342,#343,#344,#345,#346,#347,#348,#349,#350,#351,#352,#353,#354,#355,#356,#357,#358,#359,#360,
#361,#362,#363,#364,#365,#366,#367,#368,#369,#370,#371,#372,#373,#374,#375,#376,#377,#378,#379,
#380,#381,#382,#383,#384,#385,#386,#387,#388,#389,#390,#391,#392,#393,#394,#395,#396,#397,#398,
#399,#400,#401,#402,#403,#404,#405,#406,#407,#408,#409,#410,#411,#412,#413,#414,#415,#416,#417,
#418,#419,#420,#421,#422,#423,#424,#425,#426,#427,#428,#429,#430,#431,#432,#433,#434,#435,#436,
#437,#438,#439,#440,#441,#442,#443,#444,#445,#446,#447,#448,#449,#450,#451,#452,#453,#454,#455,
#456,#457,#458,#459,#460,#461,#462,#463,#464),.UNSPECIFIED.,.T.,.F.,(4,2,2,2,2,2,2,2,2,2,2,2,2,
2,2,2,2,2,2,2,2,2,2,2,2,2,2,2,2,2,2,2,2,2,2,2,2,2,2,2,2,2,2,2,2,2,2,2,2,2,2,2,2,2,2,2,2,2,2,2,2,
2,2,2,2,2,2,2,2,2,2,2,2,2,2,2,2,2,2,2,2,2,2,2,2,4),(0.,2.39078548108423,4.78154971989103,
7.17317539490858,9.56483819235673,11.9450778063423,14.3253032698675,16.705540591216,
19.0858940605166,21.6685957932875,24.2514150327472,26.8376919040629,29.4241216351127,
32.4213911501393,35.4193450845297,38.4131964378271,41.4055979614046,43.5302529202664,
45.6545607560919,47.7756897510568,49.8968295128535,52.026912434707,54.1570022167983,
56.2886771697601,58.4203924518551,60.4549416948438,62.4902787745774,64.5258256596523,
66.5609218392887,69.0115135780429,71.4623397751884,73.9158634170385,76.3695509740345,
79.3583639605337,82.347729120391,85.334918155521,88.3212851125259,90.723346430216,
93.1251281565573,95.5252887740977,97.9254857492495,100.336347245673,102.747212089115,
105.15795800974,107.568597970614,109.806709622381,112.044693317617,114.282823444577,
116.521072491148,118.892414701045,121.263826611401,123.636271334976,126.008982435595,
127.383555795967,128.757858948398,131.506587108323,134.257248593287,137.007639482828,
139.536885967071,142.066179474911,144.591748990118,147.116723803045,149.179619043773,
151.242263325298,153.302942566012,155.363650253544,157.425856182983,159.488045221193,
161.552592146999,163.617403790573,166.225696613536,168.834705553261,171.446524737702,
174.058208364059,176.717986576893,179.377756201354,182.038287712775,184.699048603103,
187.75493093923,190.811255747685,193.86403069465,196.915778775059,199.330510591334,
201.744876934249,204.15761954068,206.570410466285),.UNSPECIFIED.);
#466=CARTESIAN_POINT('',(81.75,0.,47.5));
#467=VERTEX_POINT('',#466);
#468=EDGE_CURVE('E141',#467,#467,#465,.T.);
#469=ORIENTED_EDGE('',*,*,#468,.T.);
#470=EDGE_LOOP('',(#469));
#471=FACE_BOUND('',#470,.T.);
#472=ORIENTED_EDGE('',*,*,#263,.F.);
#473=EDGE_LOOP('',(#472));
#474=FACE_BOUND('',#473,.T.);
#475=ORIENTED_EDGE('',*,*,#280,.T.);
#476=EDGE_LOOP('',(#475));
#477=FACE_BOUND('',#476,.T.);
#478=ADVANCED_FACE('F158',(#471,#474,#477),#292,.T.);
#479=CARTESIAN_POINT('',(33.,0.,0.));
#480=DIRECTION('',(-1.,0.,0.));
#481=DIRECTION('',(0.,0.,1.));
#482=AXIS2_PLACEMENT_3D('',#479,#480,#481);
#483=PLANE('',#482);
#484=CARTESIAN_POINT('',(33.,0.,0.));
#485=DIRECTION('',(-1.,0.,0.));
#486=DIRECTION('',(0.,0.,1.));
#487=AXIS2_PLACEMENT_3D('',#484,#485,#486);
#488=CIRCLE('',#487,24.);
#489=CARTESIAN_POINT('',(33.,0.,24.));
#490=VERTEX_POINT('',#489);
#491=EDGE_CURVE('E202',#490,#490,#488,.T.);
#492=ORIENTED_EDGE('',*,*,#491,.T.);
#493=EDGE_LOOP('',(#492));
#494=FACE_BOUND('',#493,.T.);
#495=CARTESIAN_POINT('',(33.,31.4800234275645,18.1749999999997));
#496=DIRECTION('',(1.,0.,0.));
#497=DIRECTION('',(0.,0.,-1.));
#498=AXIS2_PLACEMENT_3D('',#495,#496,#497);
#499=CIRCLE('',#498,2.1);
#500=CARTESIAN_POINT('',(33.,31.4800234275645,16.0749999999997));
#501=VERTEX_POINT('',#500);
#502=EDGE_CURVE('E108',#501,#501,#499,.T.);
#503=ORIENTED_EDGE('',*,*,#502,.F.);
#504=EDGE_LOOP('',(#503));
#505=FACE_BOUND('',#504,.T.);
#506=CARTESIAN_POINT('',(33.,-31.4800234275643,18.1750000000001));
#507=DIRECTION('',(1.,0.,0.));
#508=DIRECTION('',(0.,0.,-1.));
#509=AXIS2_PLACEMENT_3D('',#506,#507,#508);
#510=CIRCLE('',#509,2.1);
#511=CARTESIAN_POINT('',(33.,-31.4800234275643,16.0750000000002));
#512=VERTEX_POINT('',#511);
#513=EDGE_CURVE('E116',#512,#512,#510,.T.);
#514=ORIENTED_EDGE('',*,*,#513,.F.);
#515=EDGE_LOOP('',(#514));
#516=FACE_BOUND('',#515,.T.);
#517=CARTESIAN_POINT('',(33.,0.,-36.35));
#518=DIRECTION('',(1.,0.,0.));
#519=DIRECTION('',(0.,0.,-1.));
#520=AXIS2_PLACEMENT_3D('',#517,#518,#519);
#521=CIRCLE('',#520,2.1);
#522=CARTESIAN_POINT('',(33.,0.,-38.45));
#523=VERTEX_POINT('',#522);
#524=EDGE_CURVE('E122',#523,#523,#521,.T.);
#525=ORIENTED_EDGE('',*,*,#524,.F.);
#526=EDGE_LOOP('',(#525));
#527=FACE_BOUND('',#526,.T.);
#528=DIRECTION('',(0.,1.,0.));
#529=VECTOR('',#528,1.);
#530=CARTESIAN_POINT('',(33.,0.,27.5));
#531=LINE('',#530,#529);
#532=CARTESIAN_POINT('',(33.,-26.8153407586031,27.5));
#533=VERTEX_POINT('',#532);
#534=CARTESIAN_POINT('',(33.,26.8153407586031,27.5));
#535=VERTEX_POINT('',#534);
#536=EDGE_CURVE('E194',#533,#535,#531,.T.);
#537=ORIENTED_EDGE('',*,*,#536,.F.);
#538=DIRECTION('',(0.,0.,1.));
#539=VECTOR('',#538,1.);
#540=CARTESIAN_POINT('',(33.,-26.8153407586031,27.5));
#541=LINE('',#540,#539);
#542=EDGE_CURVE('E186',#533,#171,#541,.T.);
#543=ORIENTED_EDGE('',*,*,#542,.T.);
#544=ORIENTED_EDGE('',*,*,#179,.F.);
#545=DIRECTION('',(0.,0.,1.));
#546=VECTOR('',#545,1.);
#547=CARTESIAN_POINT('',(33.,26.8153407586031,27.5));
#548=LINE('',#547,#546);
#549=EDGE_CURVE('E185',#169,#535,#548,.F.);
#550=ORIENTED_EDGE('',*,*,#549,.T.);
#551=EDGE_LOOP('',(#537,#543,#544,#550));
#552=FACE_BOUND('',#551,.T.);
#553=ADVANCED_FACE('F154',(#494,#505,#516,#527,#552),#483,.F.);
#554=CARTESIAN_POINT('',(50.,0.,27.5));
#555=DIRECTION('',(0.,0.,1.));
#556=DIRECTION('',(1.,0.,0.));
#557=AXIS2_PLACEMENT_3D('',#554,#555,#556);
#558=CYLINDRICAL_SURFACE('',#557,31.75);
#559=CARTESIAN_POINT('',(50.,0.,27.5));
#560=DIRECTION('',(0.,0.,1.));
#561=DIRECTION('',(1.,0.,0.));
#562=AXIS2_PLACEMENT_3D('',#559,#560,#561);
#563=CIRCLE('',#562,31.75);
#564=EDGE_CURVE('E53',#535,#533,#563,.T.);
#565=ORIENTED_EDGE('',*,*,#564,.F.);
#566=ORIENTED_EDGE('',*,*,#549,.F.);
#567=ORIENTED_EDGE('',*,*,#172,.T.);
#568=ORIENTED_EDGE('',*,*,#542,.F.);
#569=EDGE_LOOP('',(#565,#566,#567,#568));
#570=FACE_BOUND('',#569,.T.);
#571=ORIENTED_EDGE('',*,*,#468,.F.);
#572=EDGE_LOOP('',(#571));
#573=FACE_BOUND('',#572,.T.);
#574=ADVANCED_FACE('F149',(#570,#573),#558,.F.);
#575=CARTESIAN_POINT('',(50.,0.,27.5));
#576=DIRECTION('',(0.,0.,1.));
#577=DIRECTION('',(1.,0.,0.));
#578=AXIS2_PLACEMENT_3D('',#575,#576,#577);
#579=PLANE('',#578);
#580=ORIENTED_EDGE('',*,*,#536,.T.);
#581=ORIENTED_EDGE('',*,*,#564,.T.);
#582=EDGE_LOOP('',(#580,#581));
#583=FACE_BOUND('',#582,.T.);
#584=ADVANCED_FACE('F153',(#583),#579,.T.);
#585=CARTESIAN_POINT('',(26.,0.,0.));
#586=DIRECTION('',(1.,0.,0.));
#587=DIRECTION('',(0.,0.,-1.));
#588=AXIS2_PLACEMENT_3D('',#585,#586,#587);
#589=CYLINDRICAL_SURFACE('',#588,23.5);
#590=CARTESIAN_POINT('',(32.5,0.,0.));
#591=DIRECTION('',(-1.,0.,0.));
#592=DIRECTION('',(0.,0.,1.));
#593=AXIS2_PLACEMENT_3D('',#590,#591,#592);
#594=CIRCLE('',#593,23.5);
#595=CARTESIAN_POINT('',(32.5,0.,23.5));
#596=VERTEX_POINT('',#595);
#597=EDGE_CURVE('E199',#596,#596,#594,.F.);
#598=ORIENTED_EDGE('',*,*,#597,.T.);
#599=EDGE_LOOP('',(#598));
#600=FACE_BOUND('',#599,.T.);
#601=CARTESIAN_POINT('',(26.,0.,0.));
#602=DIRECTION('',(1.,0.,0.));
#603=DIRECTION('',(0.,0.,-1.));
#604=AXIS2_PLACEMENT_3D('',#601,#602,#603);
#605=CIRCLE('',#604,23.5);
#606=CARTESIAN_POINT('',(26.,0.,-23.5));
#607=VERTEX_POINT('',#606);
#608=EDGE_CURVE('E131',#607,#607,#605,.T.);
#609=ORIENTED_EDGE('',*,*,#608,.F.);
#610=EDGE_LOOP('',(#609));
#611=FACE_BOUND('',#610,.T.);
#612=ADVANCED_FACE('F313',(#600,#611),#589,.F.);
#613=CARTESIAN_POINT('',(26.,0.,0.));
#614=DIRECTION('',(1.,0.,0.));
#615=DIRECTION('',(0.,0.,-1.));
#616=AXIS2_PLACEMENT_3D('',#613,#614,#615);
#617=PLANE('',#616);
#618=CARTESIAN_POINT('',(26.,0.,0.));
#619=DIRECTION('',(1.,0.,0.));
#620=DIRECTION('',(0.,0.,-1.));
#621=AXIS2_PLACEMENT_3D('',#618,#619,#620);
#622=CIRCLE('',#621,23.);
#623=CARTESIAN_POINT('',(26.,0.,-23.));
#624=VERTEX_POINT('',#623);
#625=EDGE_CURVE('E207',#624,#624,#622,.F.);
#626=ORIENTED_EDGE('',*,*,#625,.T.);
#627=EDGE_LOOP('',(#626));
#628=FACE_BOUND('',#627,.T.);
#629=ORIENTED_EDGE('',*,*,#608,.T.);
#630=EDGE_LOOP('',(#629));
#631=FACE_BOUND('',#630,.T.);
#632=ADVANCED_FACE('F310',(#628,#631),#617,.T.);
#633=CARTESIAN_POINT('',(-9.,0.,0.));
#634=DIRECTION('',(1.,0.,0.));
#635=DIRECTION('',(0.,0.,-1.));
#636=AXIS2_PLACEMENT_3D('',#633,#634,#635);
#637=CYLINDRICAL_SURFACE('',#636,22.5);
#638=CARTESIAN_POINT('',(25.5,0.,0.));
#639=DIRECTION('',(1.,0.,0.));
#640=DIRECTION('',(0.,0.,-1.));
#641=AXIS2_PLACEMENT_3D('',#638,#639,#640);
#642=CIRCLE('',#641,22.5);
#643=CARTESIAN_POINT('',(25.5,0.,-22.5));
#644=VERTEX_POINT('',#643);
#645=EDGE_CURVE('E204',#644,#644,#642,.T.);
#646=ORIENTED_EDGE('',*,*,#645,.T.);
#647=EDGE_LOOP('',(#646));
#648=FACE_BOUND('',#647,.T.);
#649=CARTESIAN_POINT('',(-9.,0.,0.));
#650=DIRECTION('',(1.,0.,0.));
#651=DIRECTION('',(0.,0.,-1.));
#652=AXIS2_PLACEMENT_3D('',#649,#650,#651);
#653=CIRCLE('',#652,22.5);
#654=CARTESIAN_POINT('',(-9.,0.,-22.5));
#655=VERTEX_POINT('',#654);
#656=EDGE_CURVE('E128',#655,#655,#653,.T.);
#657=ORIENTED_EDGE('',*,*,#656,.F.);
#658=EDGE_LOOP('',(#657));
#659=FACE_BOUND('',#658,.T.);
#660=ADVANCED_FACE('F306',(#648,#659),#637,.F.);
#661=CARTESIAN_POINT('',(-9.,0.,0.));
#662=DIRECTION('',(1.,0.,0.));
#663=DIRECTION('',(0.,0.,-1.));
#664=AXIS2_PLACEMENT_3D('',#661,#662,#663);
#665=PLANE('',#664);
#666=CARTESIAN_POINT('',(-9.,0.,0.));
#667=DIRECTION('',(1.,0.,0.));
#668=DIRECTION('',(0.,0.,-1.));
#669=AXIS2_PLACEMENT_3D('',#666,#667,#668);
#670=CIRCLE('',#669,21.);
#671=CARTESIAN_POINT('',(-9.,0.,-21.));
#672=VERTEX_POINT('',#671);
#673=EDGE_CURVE('E104',#672,#672,#670,.T.);
#674=ORIENTED_EDGE('',*,*,#673,.F.);
#675=EDGE_LOOP('',(#674));
#676=FACE_BOUND('',#675,.T.);
#677=ORIENTED_EDGE('',*,*,#656,.T.);
#678=EDGE_LOOP('',(#677));
#679=FACE_BOUND('',#678,.T.);
#680=ADVANCED_FACE('F302',(#676,#679),#665,.T.);
#681=CARTESIAN_POINT('',(19.,0.,-36.35));
#682=DIRECTION('',(1.,0.,0.));
#683=DIRECTION('',(0.,0.,-1.));
#684=AXIS2_PLACEMENT_3D('',#681,#682,#683);
#685=CONICAL_SURFACE('',#684,2.1,1.02974425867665);
#686=CARTESIAN_POINT('',(17.7381927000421,0.,-36.35));
#687=VERTEX_POINT('',#686);
#688=VERTEX_LOOP('',#687);
#689=FACE_BOUND('',#688,.T.);
#690=CARTESIAN_POINT('',(19.,0.,-36.35));
#691=DIRECTION('',(1.,0.,0.));
#692=DIRECTION('',(0.,0.,-1.));
#693=AXIS2_PLACEMENT_3D('',#690,#691,#692);
#694=CIRCLE('',#693,2.1);
#695=CARTESIAN_POINT('',(19.,0.,-38.45));
#696=VERTEX_POINT('',#695);
#697=EDGE_CURVE('E125',#696,#696,#694,.T.);
#698=ORIENTED_EDGE('',*,*,#697,.T.);
#699=EDGE_LOOP('',(#698));
#700=FACE_BOUND('',#699,.T.);
#701=ADVANCED_FACE('F298',(#689,#700),#685,.F.);
#702=CARTESIAN_POINT('',(33.,0.,-36.35));
#703=DIRECTION('',(1.,0.,0.));
#704=DIRECTION('',(0.,0.,-1.));
#705=AXIS2_PLACEMENT_3D('',#702,#703,#704);
#706=CYLINDRICAL_SURFACE('',#705,2.1);
#707=ORIENTED_EDGE('',*,*,#697,.F.);
#708=EDGE_LOOP('',(#707));
#709=FACE_BOUND('',#708,.T.);
#710=ORIENTED_EDGE('',*,*,#524,.T.);
#711=EDGE_LOOP('',(#710));
#712=FACE_BOUND('',#711,.T.);
#713=ADVANCED_FACE('F294',(#709,#712),#706,.F.);
#714=CARTESIAN_POINT('',(19.,-31.4800234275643,18.1750000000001));
#715=DIRECTION('',(1.,0.,0.));
#716=DIRECTION('',(0.,0.,-1.));
#717=AXIS2_PLACEMENT_3D('',#714,#715,#716);
#718=CONICAL_SURFACE('',#717,2.1,1.02974425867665);
#719=CARTESIAN_POINT('',(17.7381927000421,-31.4800234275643,18.1750000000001));
#720=VERTEX_POINT('',#719);
#721=VERTEX_LOOP('',#720);
#722=FACE_BOUND('',#721,.T.);
#723=CARTESIAN_POINT('',(19.,-31.4800234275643,18.1750000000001));
#724=DIRECTION('',(1.,0.,0.));
#725=DIRECTION('',(0.,0.,-1.));
#726=AXIS2_PLACEMENT_3D('',#723,#724,#725);
#727=CIRCLE('',#726,2.1);
#728=CARTESIAN_POINT('',(19.,-31.4800234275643,16.0750000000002));
#729=VERTEX_POINT('',#728);
#730=EDGE_CURVE('E119',#729,#729,#727,.T.);
#731=ORIENTED_EDGE('',*,*,#730,.T.);
#732=EDGE_LOOP('',(#731));
#733=FACE_BOUND('',#732,.T.);
#734=ADVANCED_FACE('F290',(#722,#733),#718,.F.);
#735=CARTESIAN_POINT('',(33.,-31.4800234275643,18.1750000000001));
#736=DIRECTION('',(1.,0.,0.));
#737=DIRECTION('',(0.,0.,-1.));
#738=AXIS2_PLACEMENT_3D('',#735,#736,#737);
#739=CYLINDRICAL_SURFACE('',#738,2.1);
#740=ORIENTED_EDGE('',*,*,#730,.F.);
#741=EDGE_LOOP('',(#740));
#742=FACE_BOUND('',#741,.T.);
#743=ORIENTED_EDGE('',*,*,#513,.T.);
#744=EDGE_LOOP('',(#743));
#745=FACE_BOUND('',#744,.T.);
#746=ADVANCED_FACE('F286',(#742,#745),#739,.F.);
#747=CARTESIAN_POINT('',(19.,31.4800234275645,18.1749999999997));
#748=DIRECTION('',(1.,0.,0.));
#749=DIRECTION('',(0.,0.,-1.));
#750=AXIS2_PLACEMENT_3D('',#747,#748,#749);
#751=CONICAL_SURFACE('',#750,2.1,1.02974425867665);
#752=CARTESIAN_POINT('',(17.7381927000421,31.4800234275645,18.1749999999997));
#753=VERTEX_POINT('',#752);
#754=VERTEX_LOOP('',#753);
#755=FACE_BOUND('',#754,.T.);
#756=CARTESIAN_POINT('',(19.,31.4800234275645,18.1749999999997));
#757=DIRECTION('',(1.,0.,0.));
#758=DIRECTION('',(0.,0.,-1.));
#759=AXIS2_PLACEMENT_3D('',#756,#757,#758);
#760=CIRCLE('',#759,2.1);
#761=CARTESIAN_POINT('',(19.,31.4800234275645,16.0749999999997));
#762=VERTEX_POINT('',#761);
#763=EDGE_CURVE('E113',#762,#762,#760,.T.);
#764=ORIENTED_EDGE('',*,*,#763,.T.);
#765=EDGE_LOOP('',(#764));
#766=FACE_BOUND('',#765,.T.);
#767=ADVANCED_FACE('F282',(#755,#766),#751,.F.);
#768=CARTESIAN_POINT('',(33.,31.4800234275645,18.1749999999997));
#769=DIRECTION('',(1.,0.,0.));
#770=DIRECTION('',(0.,0.,-1.));
#771=AXIS2_PLACEMENT_3D('',#768,#769,#770);
#772=CYLINDRICAL_SURFACE('',#771,2.1);
#773=ORIENTED_EDGE('',*,*,#763,.F.);
#774=EDGE_LOOP('',(#773));
#775=FACE_BOUND('',#774,.T.);
#776=ORIENTED_EDGE('',*,*,#502,.T.);
#777=EDGE_LOOP('',(#776));
#778=FACE_BOUND('',#777,.T.);
#779=ADVANCED_FACE('F278',(#775,#778),#772,.F.);
#780=CARTESIAN_POINT('',(-21.,0.,0.));
#781=DIRECTION('',(1.,0.,0.));
#782=DIRECTION('',(0.,0.,-1.));
#783=AXIS2_PLACEMENT_3D('',#780,#781,#782);
#784=CYLINDRICAL_SURFACE('',#783,21.);
#785=CARTESIAN_POINT('',(-21.,0.,0.));
#786=DIRECTION('',(1.,0.,0.));
#787=DIRECTION('',(0.,0.,-1.));
#788=AXIS2_PLACEMENT_3D('',#785,#786,#787);
#789=CIRCLE('',#788,21.);
#790=CARTESIAN_POINT('',(-21.,0.,-21.));
#791=VERTEX_POINT('',#790);
#792=EDGE_CURVE('E105',#791,#791,#789,.T.);
#793=ORIENTED_EDGE('',*,*,#792,.F.);
#794=EDGE_LOOP('',(#793));
#795=FACE_BOUND('',#794,.T.);
#796=ORIENTED_EDGE('',*,*,#673,.T.);
#797=EDGE_LOOP('',(#796));
#798=FACE_BOUND('',#797,.T.);
#799=ADVANCED_FACE('F275',(#795,#798),#784,.F.);
#800=CARTESIAN_POINT('',(-21.,0.,0.));
#801=DIRECTION('',(1.,0.,0.));
#802=DIRECTION('',(0.,0.,-1.));
#803=AXIS2_PLACEMENT_3D('',#800,#801,#802);
#804=PLANE('',#803);
#805=CARTESIAN_POINT('',(-21.,0.,0.));
#806=DIRECTION('',(1.,0.,0.));
#807=DIRECTION('',(0.,0.,-1.));
#808=AXIS2_PLACEMENT_3D('',#805,#806,#807);
#809=CIRCLE('',#808,14.);
#810=CARTESIAN_POINT('',(-21.,0.,-14.));
#811=VERTEX_POINT('',#810);
#812=EDGE_CURVE('E231',#811,#811,#809,.F.);
#813=ORIENTED_EDGE('',*,*,#812,.T.);
#814=EDGE_LOOP('',(#813));
#815=FACE_BOUND('',#814,.T.);
#816=ORIENTED_EDGE('',*,*,#792,.T.);
#817=EDGE_LOOP('',(#816));
#818=FACE_BOUND('',#817,.T.);
#819=ADVANCED_FACE('F236',(#815,#818),#804,.T.);
#820=CARTESIAN_POINT('',(32.5,0.,0.));
#821=DIRECTION('',(1.,0.,0.));
#822=DIRECTION('',(0.,0.,-1.));
#823=AXIS2_PLACEMENT_3D('',#820,#821,#822);
#824=CONICAL_SURFACE('',#823,23.5,0.785398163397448);
#825=ORIENTED_EDGE('',*,*,#491,.F.);
#826=EDGE_LOOP('',(#825));
#827=FACE_BOUND('',#826,.T.);
#828=ORIENTED_EDGE('',*,*,#597,.F.);
#829=EDGE_LOOP('',(#828));
#830=FACE_BOUND('',#829,.T.);
#831=ADVANCED_FACE('F274',(#827,#830),#824,.F.);
#832=CARTESIAN_POINT('',(25.5,0.,0.));
#833=DIRECTION('',(1.,0.,0.));
#834=DIRECTION('',(0.,0.,-1.));
#835=AXIS2_PLACEMENT_3D('',#832,#833,#834);
#836=CONICAL_SURFACE('',#835,22.5,0.785398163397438);
#837=ORIENTED_EDGE('',*,*,#625,.F.);
#838=EDGE_LOOP('',(#837));
#839=FACE_BOUND('',#838,.T.);
#840=ORIENTED_EDGE('',*,*,#645,.F.);
#841=EDGE_LOOP('',(#840));
#842=FACE_BOUND('',#841,.T.);
#843=ADVANCED_FACE('F248',(#839,#842),#836,.F.);
#844=CARTESIAN_POINT('',(-23.,0.,0.));
#845=DIRECTION('',(-1.,0.,0.));
#846=DIRECTION('',(0.,0.,1.));
#847=AXIS2_PLACEMENT_3D('',#844,#845,#846);
#848=PLANE('',#847);
#849=CARTESIAN_POINT('',(-23.,0.,0.));
#850=DIRECTION('',(-1.,0.,0.));
#851=DIRECTION('',(0.,0.,1.));
#852=AXIS2_PLACEMENT_3D('',#849,#850,#851);
#853=CIRCLE('',#852,14.);
#854=CARTESIAN_POINT('',(-23.,0.,14.));
#855=VERTEX_POINT('',#854);
#856=EDGE_CURVE('E98',#855,#855,#853,.T.);
#857=ORIENTED_EDGE('',*,*,#856,.F.);
#858=EDGE_LOOP('',(#857));
#859=FACE_BOUND('',#858,.T.);
#860=ORIENTED_EDGE('',*,*,#224,.T.);
#861=EDGE_LOOP('',(#860));
#862=FACE_BOUND('',#861,.T.);
#863=ADVANCED_FACE('F242',(#859,#862),#848,.T.);
#864=CARTESIAN_POINT('',(100.001,0.,0.));
#865=DIRECTION('',(-1.,0.,0.));
#866=DIRECTION('',(0.,0.,1.));
#867=AXIS2_PLACEMENT_3D('',#864,#865,#866);
#868=CYLINDRICAL_SURFACE('',#867,14.);
#869=ORIENTED_EDGE('',*,*,#812,.F.);
#870=EDGE_LOOP('',(#869));
#871=FACE_BOUND('',#870,.T.);
#872=ORIENTED_EDGE('',*,*,#856,.T.);
#873=EDGE_LOOP('',(#872));
#874=FACE_BOUND('',#873,.T.);
#875=ADVANCED_FACE('F239',(#871,#874),#868,.F.);
#876=CARTESIAN_POINT('',(-43.5,0.,0.));
#877=DIRECTION('',(-1.,0.,0.));
#878=DIRECTION('',(0.,0.,1.));
#879=AXIS2_PLACEMENT_3D('',#876,#877,#878);
#880=PLANE('',#879);
#881=CARTESIAN_POINT('',(-43.5,0.,-28.));
#882=DIRECTION('',(-1.,0.,0.));
#883=DIRECTION('',(0.,0.,1.));
#884=AXIS2_PLACEMENT_3D('',#881,#882,#883);
#885=CIRCLE('',#884,2.09999999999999);
#886=CARTESIAN_POINT('',(-43.5,0.,-25.9));
#887=VERTEX_POINT('',#886);
#888=EDGE_CURVE('E212',#887,#887,#885,.F.);
#889=ORIENTED_EDGE('',*,*,#888,.T.);
#890=EDGE_LOOP('',(#889));
#891=FACE_BOUND('',#890,.T.);
#892=ORIENTED_EDGE('',*,*,#207,.T.);
#893=EDGE_LOOP('',(#892));
#894=FACE_BOUND('',#893,.T.);
#895=ORIENTED_EDGE('',*,*,#235,.T.);
#896=EDGE_LOOP('',(#895));
#897=FACE_BOUND('',#896,.T.);
#898=CARTESIAN_POINT('',(-43.5,0.,28.));
#899=DIRECTION('',(-1.,0.,0.));
#900=DIRECTION('',(0.,0.,1.));
#901=AXIS2_PLACEMENT_3D('',#898,#899,#900);
#902=CIRCLE('',#901,2.09999999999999);
#903=CARTESIAN_POINT('',(-43.5,0.,30.1));
#904=VERTEX_POINT('',#903);
#905=EDGE_CURVE('E217',#904,#904,#902,.F.);
#906=ORIENTED_EDGE('',*,*,#905,.T.);
#907=EDGE_LOOP('',(#906));
#908=FACE_BOUND('',#907,.T.);
#909=ADVANCED_FACE('F85',(#891,#894,#897,#908),#880,.T.);
#910=CARTESIAN_POINT('',(-32.,0.,-28.));
#911=DIRECTION('',(-1.,0.,0.));
#912=DIRECTION('',(0.,0.,1.));
#913=AXIS2_PLACEMENT_3D('',#910,#911,#912);
#914=CONICAL_SURFACE('',#913,2.09999999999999,1.02974425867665);
#915=CARTESIAN_POINT('',(-30.7381927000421,0.,-28.));
#916=VERTEX_POINT('',#915);
#917=VERTEX_LOOP('',#916);
#918=FACE_BOUND('',#917,.T.);
#919=CARTESIAN_POINT('',(-32.,0.,-28.));
#920=DIRECTION('',(-1.,0.,0.));
#921=DIRECTION('',(0.,0.,1.));
#922=AXIS2_PLACEMENT_3D('',#919,#920,#921);
#923=CIRCLE('',#922,2.09999999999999);
#924=CARTESIAN_POINT('',(-32.,0.,-25.9));
#925=VERTEX_POINT('',#924);
#926=EDGE_CURVE('E89',#925,#925,#923,.T.);
#927=ORIENTED_EDGE('',*,*,#926,.T.);
#928=EDGE_LOOP('',(#927));
#929=FACE_BOUND('',#928,.T.);
#930=ADVANCED_FACE('F81',(#918,#929),#914,.F.);
#931=CARTESIAN_POINT('',(-46.,0.,-28.));
#932=DIRECTION('',(-1.,0.,0.));
#933=DIRECTION('',(0.,0.,1.));
#934=AXIS2_PLACEMENT_3D('',#931,#932,#933);
#935=CYLINDRICAL_SURFACE('',#934,2.09999999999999);
#936=ORIENTED_EDGE('',*,*,#926,.F.);
#937=EDGE_LOOP('',(#936));
#938=FACE_BOUND('',#937,.T.);
#939=ORIENTED_EDGE('',*,*,#888,.F.);
#940=EDGE_LOOP('',(#939));
#941=FACE_BOUND('',#940,.T.);
#942=ADVANCED_FACE('F84',(#938,#941),#935,.F.);
#943=CARTESIAN_POINT('',(-32.,0.,28.));
#944=DIRECTION('',(-1.,0.,0.));
#945=DIRECTION('',(0.,0.,1.));
#946=AXIS2_PLACEMENT_3D('',#943,#944,#945);
#947=CONICAL_SURFACE('',#946,2.09999999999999,1.02974425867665);
#948=CARTESIAN_POINT('',(-30.7381927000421,0.,28.));
#949=VERTEX_POINT('',#948);
#950=VERTEX_LOOP('',#949);
#951=FACE_BOUND('',#950,.T.);
#952=CARTESIAN_POINT('',(-32.,0.,28.));
#953=DIRECTION('',(-1.,0.,0.));
#954=DIRECTION('',(0.,0.,1.));
#955=AXIS2_PLACEMENT_3D('',#952,#953,#954);
#956=CIRCLE('',#955,2.09999999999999);
#957=CARTESIAN_POINT('',(-32.,0.,30.1));
#958=VERTEX_POINT('',#957);
#959=EDGE_CURVE('E91',#958,#958,#956,.T.);
#960=ORIENTED_EDGE('',*,*,#959,.T.);
#961=EDGE_LOOP('',(#960));
#962=FACE_BOUND('',#961,.T.);
#963=ADVANCED_FACE('F262',(#951,#962),#947,.F.);
#964=CARTESIAN_POINT('',(-46.,0.,28.));
#965=DIRECTION('',(-1.,0.,0.));
#966=DIRECTION('',(0.,0.,1.));
#967=AXIS2_PLACEMENT_3D('',#964,#965,#966);
#968=CYLINDRICAL_SURFACE('',#967,2.09999999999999);
#969=ORIENTED_EDGE('',*,*,#959,.F.);
#970=EDGE_LOOP('',(#969));
#971=FACE_BOUND('',#970,.T.);
#972=ORIENTED_EDGE('',*,*,#905,.F.);
#973=EDGE_LOOP('',(#972));
#974=FACE_BOUND('',#973,.T.);
#975=ADVANCED_FACE('F264',(#971,#974),#968,.F.);
#976=CARTESIAN_POINT('',(97.,0.,0.));
#977=DIRECTION('',(1.,0.,0.));
#978=DIRECTION('',(0.,0.,-1.));
#979=AXIS2_PLACEMENT_3D('',#976,#977,#978);
#980=CYLINDRICAL_SURFACE('',#979,44.9);
#981=CARTESIAN_POINT('',(97.,0.,0.));
#982=DIRECTION('',(1.,0.,0.));
#983=DIRECTION('',(0.,0.,-1.));
#984=AXIS2_PLACEMENT_3D('',#981,#982,#983);
#985=CIRCLE('',#984,44.9);
#986=CARTESIAN_POINT('',(97.,0.,-44.9));
#987=VERTEX_POINT('',#986);
#988=EDGE_CURVE('E220',#987,#987,#985,.T.);
#989=ORIENTED_EDGE('',*,*,#988,.F.);
#990=EDGE_LOOP('',(#989));
#991=FACE_BOUND('',#990,.T.);
#992=ORIENTED_EDGE('',*,*,#252,.T.);
#993=EDGE_LOOP('',(#992));
#994=FACE_BOUND('',#993,.T.);
#995=ADVANCED_FACE('F267',(#991,#994),#980,.F.);
#996=CARTESIAN_POINT('',(97.,0.,0.));
#997=DIRECTION('',(1.,0.,0.));
#998=DIRECTION('',(0.,0.,-1.));
#999=AXIS2_PLACEMENT_3D('',#996,#997,#998);
#1000=PLANE('',#999);
#1001=CARTESIAN_POINT('',(97.,0.,0.));
#1002=DIRECTION('',(1.,0.,0.));
#1003=DIRECTION('',(0.,0.,-1.));
#1004=AXIS2_PLACEMENT_3D('',#1001,#1002,#1003);
#1005=CIRCLE('',#1004,43.);
#1006=CARTESIAN_POINT('',(97.,0.,-43.));
#1007=VERTEX_POINT('',#1006);
#1008=EDGE_CURVE('E12',#1007,#1007,#1005,.F.);
#1009=ORIENTED_EDGE('',*,*,#1008,.T.);
#1010=EDGE_LOOP('',(#1009));
#1011=FACE_BOUND('',#1010,.T.);
#1012=ORIENTED_EDGE('',*,*,#988,.T.);
#1013=EDGE_LOOP('',(#1012));
#1014=FACE_BOUND('',#1013,.T.);
#1015=ADVANCED_FACE('F486',(#1011,#1014),#1000,.T.);
#1016=CARTESIAN_POINT('',(96.5,0.,0.));
#1017=DIRECTION('',(1.,0.,0.));
#1018=DIRECTION('',(0.,0.,-1.));
#1019=AXIS2_PLACEMENT_3D('',#1016,#1017,#1018);
#1020=CONICAL_SURFACE('',#1019,42.5,0.785398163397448);
#1021=ORIENTED_EDGE('',*,*,#1008,.F.);
#1022=EDGE_LOOP('',(#1021));
#1023=FACE_BOUND('',#1022,.T.);
#1024=ORIENTED_EDGE('',*,*,#31,.F.);
#1025=EDGE_LOOP('',(#1024));
#1026=FACE_BOUND('',#1025,.T.);
#1027=ADVANCED_FACE('F41',(#1023,#1026),#1020,.F.);
#1028=CLOSED_SHELL('',(#183,#211,#239,#267,#287,#478,#553,#574,#584,#612,#632,#660,#680,#701,
#713,#734,#746,#767,#779,#799,#819,#831,#843,#863,#875,#909,#930,#942,#963,#975,#995,#1015,#1027));
#1029=MANIFOLD_SOLID_BREP('B2',#1028);
#1030=ADVANCED_BREP_SHAPE_REPRESENTATION('',(#18,#1029),#14);
#1031=SHAPE_DEFINITION_REPRESENTATION(#9,#1030);
ENDSEC;
END-ISO-10303-21;
